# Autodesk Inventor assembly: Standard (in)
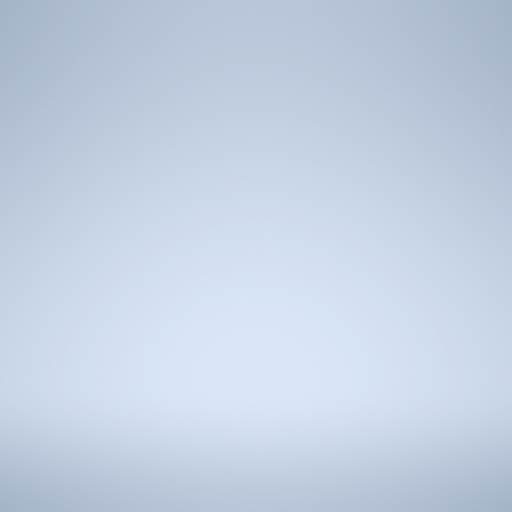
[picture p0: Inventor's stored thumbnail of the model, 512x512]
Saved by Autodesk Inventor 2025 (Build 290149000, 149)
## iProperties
Created: 2024-02
Part Number: Standard (in)
Document SubType Name: Assembly
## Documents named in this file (1)
- C:\Users\enu\Desktop\2\Standard (in).iam
